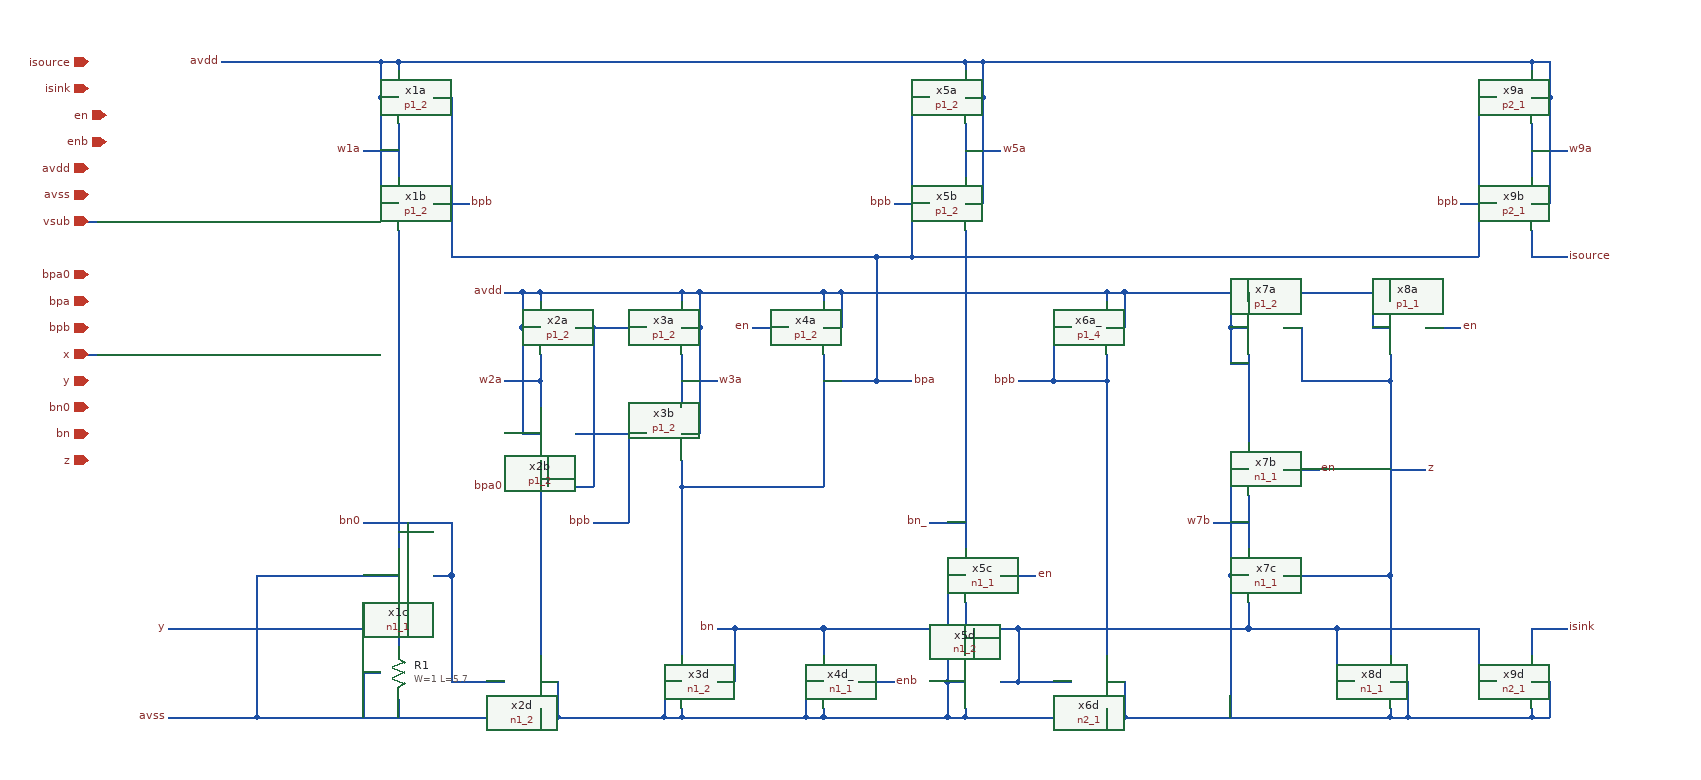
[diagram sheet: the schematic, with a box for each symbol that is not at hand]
v {xschem version=2.9.9 file_version=1.2 }
G {}
K {}
V {}
S {}
E {}
N 400 -250 400 -220 { lab=y}
N 500 -160 520 -160 { lab=bn0}
N 400 -860 400 -850 { lab=avdd}
N 380 -820 400 -820 { lab=avdd}
N 380 -860 380 -820 { lab=avdd}
N 380 -860 400 -860 { lab=avdd}
N 380 -700 400 -700 { lab=avdd}
N 560 -600 560 -590 { lab=avdd}
N 540 -560 560 -560 { lab=avdd}
N 540 -600 540 -560 { lab=avdd}
N 540 -600 560 -600 { lab=avdd}
N 540 -440 560 -440 { lab=avdd}
N 720 -560 740 -560 { lab=avdd}
N 740 -600 740 -560 { lab=avdd}
N 720 -600 740 -600 { lab=avdd}
N 720 -440 740 -440 { lab=avdd}
N 720 -600 720 -590 { lab=avdd}
N 560 -600 720 -600 { lab=avdd}
N 1040 -820 1060 -820 { lab=avdd}
N 1060 -860 1060 -820 { lab=avdd}
N 1040 -860 1060 -860 { lab=avdd}
N 1040 -700 1060 -700 { lab=avdd}
N 1040 -860 1040 -850 { lab=avdd}
N 600 -560 620 -560 { lab=bpa0}
N 620 -560 680 -560 { lab=bpa0}
N 600 -440 680 -440 { lab=bpb}
N 440 -820 460 -820 { lab=bpa}
N 460 -340 460 -280 { lab=bn0}
N 440 -280 460 -280 { lab=bn0}
N 460 -280 460 -160 { lab=bn0}
N 460 -160 500 -160 { lab=bn0}
N 240 -280 400 -280 { lab=avss}
N 560 -130 560 -120 { lab=avss}
N 720 -130 720 -120 { lab=avss}
N 700 -160 720 -160 { lab=avss}
N 700 -160 700 -120 { lab=avss}
N 560 -160 580 -160 { lab=avss}
N 580 -160 580 -120 { lab=avss}
N 560 -120 580 -120 { lab=avss}
N 700 -120 720 -120 { lab=avss}
N 580 -120 700 -120 { lab=avss}
N 260 -120 560 -120 { lab=avss}
N 240 -860 380 -860 { lab=avdd}
N 980 -820 1000 -820 { lab=bpa}
N 440 -700 480 -700 { lab=bpb}
N 960 -700 1000 -700 { lab=bpb}
N 1200 -130 1200 -120 { lab=avss}
N 1200 -160 1220 -160 { lab=avss}
N 1220 -160 1220 -120 { lab=avss}
N 1200 -120 1220 -120 { lab=avss}
N 1200 -530 1200 -500 { lab=bpb}
N 1680 -820 1700 -820 { lab=avdd}
N 1700 -860 1700 -820 { lab=avdd}
N 1680 -860 1700 -860 { lab=avdd}
N 1680 -700 1700 -700 { lab=avdd}
N 1680 -860 1680 -850 { lab=avdd}
N 1620 -820 1640 -820 { lab=bpa}
N 1600 -700 1640 -700 { lab=bpb}
N 1520 -280 1520 -190 { lab=z}
N 1520 -130 1520 -120 { lab=avss}
N 1520 -160 1540 -160 { lab=avss}
N 1540 -160 1540 -120 { lab=avss}
N 1520 -120 1540 -120 { lab=avss}
N 1200 -600 1200 -590 { lab=avdd}
N 1140 -500 1200 -500 { lab=bpb}
N 1140 -560 1140 -500 { lab=bpb}
N 1140 -560 1160 -560 { lab=bpb}
N 1200 -560 1220 -560 { lab=avdd}
N 1220 -600 1220 -560 { lab=avdd}
N 1520 -530 1520 -500 { lab=z}
N 1400 -280 1520 -280 { lab=z}
N 520 -600 540 -600 { lab=avdd}
N 1200 -600 1220 -600 { lab=avdd}
N 1360 -250 1360 -220 { lab=bn}
N 1460 -160 1480 -160 { lab=bn}
N 1460 -220 1460 -160 { lab=bn}
N 1360 -220 1460 -220 { lab=bn}
N 880 -530 880 -470 { lab=bpa}
N 800 -560 840 -560 { lab=en}
N 880 -560 900 -560 { lab=avdd}
N 900 -600 900 -560 { lab=avdd}
N 880 -600 900 -600 { lab=avdd}
N 880 -600 880 -590 { lab=avdd}
N 1360 -370 1360 -310 { lab=w7b}
N 1400 -400 1440 -400 { lab=en}
N 460 -820 460 -640 { lab=bpa}
N 980 -820 980 -640 { lab=bpa}
N 1700 -820 1700 -700 { lab=avdd}
N 1680 -790 1680 -730 { lab=w9a}
N 620 -560 620 -380 { lab=bpa0}
N 740 -560 740 -440 { lab=avdd}
N 540 -560 540 -440 { lab=avdd}
N 720 -410 720 -380 { lab=bpa}
N 720 -380 720 -190 { lab=bpa}
N 400 -670 400 -310 { lab=bn0}
N 400 -790 400 -730 { lab=w1a}
N 380 -820 380 -700 { lab=avdd}
N 1060 -820 1060 -700 { lab=avdd}
N 1040 -790 1040 -730 { lab=w5a}
N 1200 -500 1200 -190 { lab=bpb}
N 1620 -820 1620 -640 { lab=bpa}
N 660 -440 660 -340 { lab=bpb}
N 620 -340 660 -340 { lab=bpb}
N 1680 -670 1680 -640 { lab=isource}
N 1680 -640 1720 -640 { lab=isource}
N 880 -220 880 -190 { lab=bn}
N 780 -220 880 -220 { lab=bn}
N 780 -220 780 -160 { lab=bn}
N 760 -160 780 -160 { lab=bn}
N 720 -120 860 -120 { lab=avss}
N 860 -160 860 -120 { lab=avss}
N 860 -160 880 -160 { lab=avss}
N 860 -120 880 -120 { lab=avss}
N 880 -130 880 -120 { lab=avss}
N 740 -600 880 -600 { lab=avdd}
N 1080 -280 1120 -280 { lab=en}
N 1040 -250 1040 -190 { lab=bn}
N 880 -220 1100 -220 { lab=bn}
N 1100 -220 1100 -160 { lab=bn}
N 1080 -160 1100 -160 { lab=bn}
N 1100 -160 1160 -160 { lab=bn}
N 1040 -130 1040 -120 { lab=avss}
N 1040 -120 1200 -120 { lab=avss}
N 1020 -160 1040 -160 { lab=avss}
N 1020 -160 1020 -120 { lab=avss}
N 1020 -120 1040 -120 { lab=avss}
N 880 -120 1020 -120 { lab=avss}
N 720 -380 880 -380 { lab=bpa}
N 1040 -670 1040 -310 { lab=bn_}
N 1050 -220 1050 -210 { lab=bn}
N 1040 -210 1050 -210 { lab=bn}
N 360 -760 400 -760 { lab=w1a}
N 1220 -120 1520 -120 { lab=avss}
N 1100 -220 1360 -220 { lab=bn}
N 900 -600 1200 -600 { lab=avdd}
N 1520 -500 1520 -280 { lab=z}
N 1220 -600 1520 -600 { lab=avdd}
N 400 -860 1040 -860 { lab=avdd}
N 880 -500 940 -500 { lab=bpa}
N 940 -640 940 -500 { lab=bpa}
N 940 -640 980 -640 { lab=bpa}
N 460 -640 940 -640 { lab=bpa}
N 140 -220 400 -220 { lab=y}
N 360 -340 460 -340 { lab=bn0}
N 410 -340 410 -330 { lab=bn0}
N 400 -330 410 -330 { lab=bn0}
N 520 -380 620 -380 { lab=bpa0}
N 560 -410 560 -190 { lab=bpa0}
N 560 -390 570 -390 { lab=bpa0}
N 570 -390 570 -380 { lab=bpa0}
N 940 -500 980 -500 { lab=bpa}
N 520 -500 560 -500 { lab=w2a}
N 560 -500 560 -470 { lab=w2a}
N 560 -530 560 -500 { lab=w2a}
N 720 -530 720 -470 { lab=w3a}
N 720 -500 760 -500 { lab=w3a}
N 140 -120 240 -120 { lab=avss}
N 1040 -760 1080 -760 { lab=w5a}
N 1680 -760 1720 -760 { lab=w9a}
N 1100 -500 1140 -500 { lab=bpb}
N 1020 -280 1040 -280 { lab=avss}
N 1020 -280 1020 -160 { lab=avss}
N 920 -160 960 -160 { lab=enb}
N 1360 -530 1360 -430 { lab=avdd}
N 1360 -600 1360 -590 { lab=avdd}
N 1340 -560 1360 -560 { lab=avdd}
N 1340 -600 1340 -560 { lab=avdd}
N 1340 -520 1360 -520 { lab=avdd}
N 1340 -560 1340 -520 { lab=avdd}
N 1420 -500 1520 -500 { lab=z}
N 1420 -560 1420 -500 { lab=z}
N 1400 -560 1420 -560 { lab=z}
N 1520 -600 1520 -590 { lab=avdd}
N 1500 -560 1520 -560 { lab=avdd}
N 1500 -600 1500 -560 { lab=avdd}
N 1560 -560 1600 -560 { lab=en}
N 980 -640 1620 -640 { lab=bpa}
N 1060 -860 1680 -860 { lab=avdd}
N 1620 -160 1640 -160 { lab=bn}
N 1680 -130 1680 -120 { lab=avss}
N 1680 -160 1700 -160 { lab=avss}
N 1700 -160 1700 -120 { lab=avss}
N 1680 -120 1700 -120 { lab=avss}
N 1540 -120 1680 -120 { lab=avss}
N 1460 -220 1620 -220 { lab=bn}
N 1620 -220 1620 -160 { lab=bn}
N 1680 -220 1680 -190 { lab=isink}
N 1680 -220 1720 -220 { lab=isink}
N 1340 -400 1360 -400 { lab=avss}
N 1340 -400 1340 -280 { lab=avss}
N 1340 -280 1360 -280 { lab=avss}
N 1340 -280 1340 -120 { lab=avss}
N 1320 -340 1360 -340 { lab=w7b}
N 880 -470 880 -380 { lab=bpa}
N 1520 -400 1560 -400 { lab=z}
N 1000 -340 1040 -340 { lab=bn_}
N 760 -220 780 -220 { lab=bn}
N 40 -680 60 -680 { lab=vsub}
N 240 -120 260 -120 { lab=avss}
N 240 -280 240 -120 { lab=avss}
N 200 -860 240 -860 { lab=avdd}
N 400 -220 400 -200 { lab=y}
N 400 -140 400 -120 { lab=avss}
N 360 -170 380 -170 { lab=avss}
N 360 -170 360 -120 { lab=avss}
N 40 -530 60 -530 { lab=x}
C {n1_1.sym} 420 -280 0 1 {name=x1c}
C {n1_2.sym} 540 -160 0 0 {name=x2d}
C {n1_2.sym} 740 -160 0 1 {name=x3d}
C {p1_2.sym} 420 -700 0 1 {name=x1b}
C {p1_2.sym} 420 -820 0 1 {name=x1a}
C {p1_2.sym} 580 -440 0 1 {name=x2b}
C {p1_2.sym} 580 -560 0 1 {name=x2a}
C {p1_2.sym} 700 -440 0 0 {name=x3b}
C {p1_2.sym} 700 -560 0 0 {name=x3a}
C {n1_2.sym} 1060 -160 0 1 {name=x5d}
C {p1_2.sym} 1020 -700 0 0 {name=x5b}
C {p1_2.sym} 1020 -820 0 0 {name=x5a}
C {n2_1.sym} 1180 -160 0 0 {name=x6d}
C {p1_4.sym} 1180 -560 0 0 {name=x6a_}
C {p2_1.sym} 1660 -700 0 0 {name=x9b}
C {p2_1.sym} 1660 -820 0 0 {name=x9a}
C {n1_1.sym} 1500 -160 0 0 {name=x8d}
C {n1_1.sym} 1380 -280 0 1 {name=x7c}
C {n1_1.sym} 1380 -400 0 1 {name=x7b}
C {n1_1.sym} 900 -160 0 1 {name=x4d_}
C {n1_1.sym} 1060 -280 0 1 {name=x5c}
C {p1_2.sym} 860 -560 0 0 {name=x4a}
C {devices/title.sym} 160 -40 0 0 {name=l1 author="Luis Henrique Rodovalho"}
C {devices/lab_wire.sym} 480 -700 0 1 {name=l2 sig_type=std_logic lab=bpb}
C {devices/lab_wire.sym} 960 -700 0 0 {name=l4 sig_type=std_logic lab=bpb}
C {devices/lab_wire.sym} 1600 -700 0 0 {name=l5 sig_type=std_logic lab=bpb}
C {devices/lab_wire.sym} 360 -760 0 0 {name=l8 sig_type=std_logic lab=w1a}
C {devices/lab_wire.sym} 620 -340 0 0 {name=l7 sig_type=std_logic lab=bpb}
C {devices/lab_wire.sym} 140 -220 0 0 {name=l11 sig_type=std_logic lab=y}
C {devices/lab_wire.sym} 360 -340 0 0 {name=l10 sig_type=std_logic lab=bn0}
C {devices/lab_wire.sym} 520 -380 0 0 {name=l12 sig_type=std_logic lab=bpa0}
C {devices/lab_wire.sym} 980 -500 0 1 {name=l14 sig_type=std_logic lab=bpa}
C {devices/lab_wire.sym} 800 -560 0 0 {name=l16 sig_type=std_logic lab=en}
C {devices/lab_wire.sym} 520 -500 0 0 {name=l17 sig_type=std_logic lab=w2a}
C {devices/lab_wire.sym} 760 -500 0 1 {name=l18 sig_type=std_logic lab=w3a}
C {devices/lab_wire.sym} 200 -860 0 0 {name=l19 sig_type=std_logic lab=avdd}
C {devices/lab_wire.sym} 140 -120 0 0 {name=l20 sig_type=std_logic lab=avss}
C {devices/lab_wire.sym} 1080 -760 0 1 {name=l21 sig_type=std_logic lab=w5a}
C {devices/lab_wire.sym} 1720 -760 0 1 {name=l22 sig_type=std_logic lab=w9a}
C {devices/lab_wire.sym} 1100 -500 0 0 {name=l23 sig_type=std_logic lab=bpb}
C {devices/lab_wire.sym} 1120 -280 0 1 {name=l24 sig_type=std_logic lab=en}
C {devices/lab_wire.sym} 1440 -400 0 1 {name=l27 sig_type=std_logic lab=en}
C {devices/lab_wire.sym} 1600 -560 0 1 {name=l28 sig_type=std_logic lab=en}
C {devices/lab_wire.sym} 520 -600 0 0 {name=l29 sig_type=std_logic lab=avdd}
C {devices/lab_wire.sym} 1720 -640 0 1 {name=l30 sig_type=std_logic lab=isource}
C {devices/lab_wire.sym} 960 -160 0 1 {name=l31 sig_type=std_logic lab=enb}
C {p1_2.sym} 1380 -560 0 1 {name=x7a}
C {p1_1.sym} 1540 -560 0 1 {name=x8a}
C {n2_1.sym} 1660 -160 0 0 {name=x9d}
C {devices/lab_wire.sym} 1720 -220 0 1 {name=l32 sig_type=std_logic lab=isink}
C {devices/lab_wire.sym} 1320 -340 0 0 {name=l25 sig_type=std_logic lab=w7b}
C {devices/iopin.sym} 50 -830 0 0 {name=p1 lab=isink}
C {devices/iopin.sym} 50 -860 0 0 {name=p2 lab=isource}
C {devices/ipin.sym} 70 -770 0 0 {name=p3 lab=enb}
C {devices/ipin.sym} 70 -800 0 0 {name=p4 lab=en}
C {devices/iopin.sym} 50 -710 0 0 {name=p5 lab=avss}
C {devices/iopin.sym} 50 -740 0 0 {name=p6 lab=avdd}
C {devices/iopin.sym} 50 -560 0 0 {name=p7 lab=bpb}
C {devices/iopin.sym} 50 -590 0 0 {name=p8 lab=bpa}
C {devices/iopin.sym} 50 -440 0 0 {name=p9 lab=bn}
C {devices/iopin.sym} 50 -530 0 0 {name=p10 lab=x}
C {devices/iopin.sym} 50 -500 0 0 {name=p11 lab=y}
C {devices/iopin.sym} 50 -470 0 0 {name=p12 lab=bn0}
C {devices/iopin.sym} 50 -620 0 0 {name=p13 lab=bpa0}
C {devices/iopin.sym} 50 -680 0 0 {name=p14 lab=vsub}
C {devices/lab_wire.sym} 1560 -400 0 1 {name=l13 sig_type=std_logic lab=z}
C {devices/iopin.sym} 50 -410 0 0 {name=p15 lab=z}
C {devices/lab_wire.sym} 1000 -340 0 0 {name=l15 sig_type=std_logic lab=bn_}
C {devices/lab_wire.sym} 760 -220 0 0 {name=l26 sig_type=std_logic lab=bn}
C {devices/noconn.sym} 40 -680 0 0 {name=l33}
C {sky130_fd_pr/res_xhigh_po.sym} 400 -170 0 0 {name=R1
W=1
L=5.7
model=res_xhigh_po
spiceprefix=X
mult=1}
C {devices/noconn.sym} 40 -530 0 0 {name=l3}
